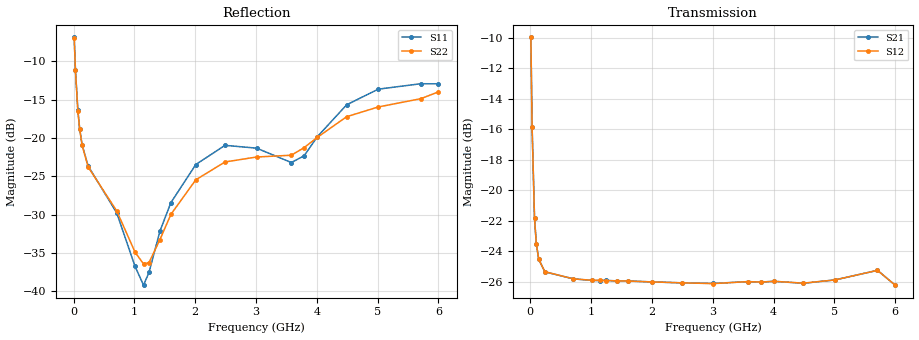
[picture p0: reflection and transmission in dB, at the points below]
! Integrated Device Technology
! Corporate Headquarters
! 6024 Silver Creek Valley Road
! San Jose, CA 95138  USA
! Phone:  1-408-284-8200
! Toll Free:  1-800-223-1366
! Webpage:  http://www.idt.com/
! Timing and RF Division
! 515 Groton Road, Suite 102
! Westford, MA 01886-6024
! Device:  F1951
! Description: 6-bit 0.5 dB Digital Step Attenuator
! Frequency:  100.0 -  4000.00 MHz
! Package:  4x4 mm Thin QFN Plastic Package: 24 pin
! Ports:  2 RF, 6 DC
!  Pin  1  = NC
!  Pin  2  = RF1  =  Port 1
!  Pin  3  = GND
!  Pin  4  = NC
!  Pin  5  = Serial Data Out (SDO)
!  Pin  6  = NC
!  Pin  7  = Reset Bar ( RSTb)
!  Pin  8  = Clock (CLK)
!  Pin  9  = Chip Select Bar (CSb)
!  Pin 10  = NC
!  Pin 11  = Serial Data In (SDI)
!  Pin 12  = NC
!  Pin 13  = NC
!  Pin 14  = VDD
!  Pin 15  = NC
!  Pin 16  = GND
!  Pin 17  = RF2  =  Port 2
!  Pin 18  = NC
!  Pin 19  = GND
!  Pin 20  = GND
!  Pin 21  = GND
!  Pin 22  = GND
!  Pin 23  = GND
!  Pin 24  = GND
! State:  50
! Atten State:  25.0 dB
! Voltage:  +3.30 Volts
! Current:  0.479 mA
! Data:  The device was measured on a F195X evaluation board which has
!  individual transmission lines to the RF pins.  Data was collected
!  de-embedded using a Automatic Fixture Removal [AFR] (Keysight Technologies).
!  The reference plane is the edge of the package pin.
! Misc:  Lot Code  1225BCA
!  Action Tracker AT0399
! Date Measured:  2018-09-13
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# GHz S dB R 50
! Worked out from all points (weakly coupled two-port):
!   600 points, 10 MHz to 6 GHz, reference 50 ohm
!   highest |S21| = -9.97 dB at 10 MHz (marker M1); lowest = -26.2 dB at 6 GHz (marker M2)
!   lowest |S11| = -39.2 dB at 1.15 GHz (marker M3), VSWR 1.02, Z = 48.9 + j0.236 ohm
!   |S11| at or under -10 dB: 24.46 MHz to end of sweep
!   |S22| runs from -36.7 to -6.9 dB; largest |S21 - S12| = 0.00017
!   S11 on the Smith chart (normalised r, x): 10 MHz: 1.82, -1.10; 30 MHz: 1.14, -0.60; 70 MHz: 0.97, -0.30; 1.24 GHz: 0.98, +0.02; 6 GHz: 0.80, +0.36
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0.01  -6.89 -31.9  -9.97 -33.8  -9.97 -33.8  -6.95 -32.0
0.03  -11.08 -61.4  -15.84 -53.9  -15.84 -54.0  -11.15 -61.5
0.07  -16.37 -86.6  -21.85 -46.5  -21.85 -46.5  -16.47 -86.8
0.1  -18.79 -97.2  -23.53 -38.0  -23.53 -37.9  -18.85 -97.5
0.14  -20.89 -107.4  -24.54 -30.2  -24.54 -30.2  -20.97 -107.3
0.24  -23.66 -121.6  -25.36 -20.7  -25.35 -20.6  -23.79 -121.9
0.71  -29.78 -133.9  -25.82 -15.0  -25.82 -15.0  -29.52 -137.5
1.01  -36.73 -152.6  -25.92 -16.8  -25.91 -16.8  -34.88 -151.8
1.15  -39.18 167.3  -25.93 -17.8  -25.92 -17.7  -36.42 -173.5
1.24  -37.53 139.8  -25.92 -18.5  -25.93 -18.5  -36.24 169.0
1.42  -32.14 118.4  -25.95 -20.3  -25.95 -20.3  -33.25 143.0
1.6  -28.43 115.5  -25.96 -22.0  -25.96 -22.0  -29.96 133.5
2.01  -23.46 123.8  -26.02 -26.5  -26.02 -26.4  -25.45 134.5
2.49  -20.96 136.9  -26.08 -31.6  -26.08 -31.6  -23.13 141.8
3.01  -21.33 147.1  -26.12 -36.9  -26.13 -36.8  -22.48 145.2
3.58  -23.20 126.3  -26.00 -42.7  -26.00 -42.7  -22.25 128.0
3.79  -22.33 110.4  -26.03 -45.0  -26.03 -44.9  -21.27 121.1
4.01  -19.82 101.6  -25.98 -47.3  -25.98 -47.2  -19.91 115.8
4.49  -15.68 99.7  -26.11 -51.9  -26.10 -51.9  -17.23 114.0
5.01  -13.64 108.5  -25.89 -55.0  -25.89 -55.0  -15.96 116.5
5.71  -12.93 113.5  -25.26 -66.2  -25.26 -66.2  -14.88 109.3
6  -12.94 107.3  -26.23 -68.7  -26.23 -68.7  -13.99 105.5
